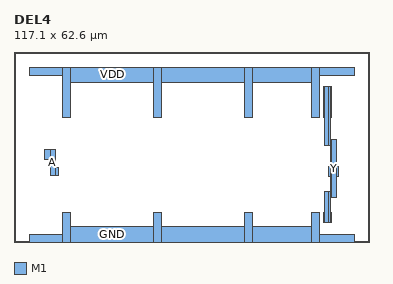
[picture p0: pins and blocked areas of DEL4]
MACRO DEL4
  CLASS CORE ;
  ORIGIN 0 0 ;
  SIZE 117.100 BY 62.600 ;
  SYMMETRY X Y ;
  SITE TR1um_site ;
  PIN VDD
    DIRECTION INOUT ;
    USE POWER ;
    PORT
      LAYER M1 ;
        RECT 5.000 55.000 16.100 57.600 ;
      LAYER M1 ;
        RECT 16.100 41.000 18.700 57.600 ;
      LAYER M1 ;
        RECT 18.700 52.600 46.100 57.600 ;
      LAYER M1 ;
        RECT 46.100 41.000 48.700 57.600 ;
      LAYER M1 ;
        RECT 48.700 52.600 76.100 57.600 ;
      LAYER M1 ;
        RECT 76.100 41.000 78.700 57.600 ;
      LAYER M1 ;
        RECT 78.700 52.600 98.100 57.600 ;
      LAYER M1 ;
        RECT 98.100 41.000 100.700 57.600 ;
      LAYER M1 ;
        RECT 100.700 55.000 112.100 57.600 ;
    END
  END VDD
  PIN Y
    DIRECTION OUTPUT ;
    USE SIGNAL ;
    PORT
      LAYER M1 ;
        RECT 102.100 6.400 102.400 9.800 ;
      LAYER M1 ;
        RECT 102.100 41.000 102.400 51.200 ;
      LAYER M1 ;
        RECT 102.400 6.400 103.600 16.600 ;
      LAYER M1 ;
        RECT 102.400 31.800 103.600 51.200 ;
      LAYER M1 ;
        RECT 103.600 6.400 104.300 16.600 ;
      LAYER M1 ;
        RECT 103.600 21.600 104.300 25.000 ;
      LAYER M1 ;
        RECT 103.600 31.800 104.300 51.200 ;
      LAYER M1 ;
        RECT 104.300 6.400 104.400 51.200 ;
      LAYER M1 ;
        RECT 104.400 6.400 104.700 9.800 ;
      LAYER M1 ;
        RECT 104.400 14.600 104.700 33.800 ;
      LAYER M1 ;
        RECT 104.400 41.000 104.700 51.200 ;
      LAYER M1 ;
        RECT 104.700 14.600 106.300 33.800 ;
      LAYER M1 ;
        RECT 106.300 21.600 107.000 25.000 ;
    END
  END Y
  PIN A
    DIRECTION INPUT ;
    USE SIGNAL ;
    PORT
      LAYER M1 ;
        RECT 10.100 27.100 11.900 30.500 ;
      LAYER M1 ;
        RECT 11.900 22.000 13.700 30.500 ;
      LAYER M1 ;
        RECT 13.700 22.000 14.500 24.600 ;
    END
  END A
  PIN GND
    DIRECTION INOUT ;
    USE GROUND ;
    PORT
      LAYER M1 ;
        RECT 5.000 0.000 16.100 2.600 ;
      LAYER M1 ;
        RECT 16.100 0.000 18.700 9.800 ;
      LAYER M1 ;
        RECT 18.700 0.000 46.100 5.000 ;
      LAYER M1 ;
        RECT 46.100 0.000 48.700 9.800 ;
      LAYER M1 ;
        RECT 48.700 0.000 76.100 5.000 ;
      LAYER M1 ;
        RECT 76.100 0.000 78.700 9.800 ;
      LAYER M1 ;
        RECT 78.700 0.000 98.100 5.000 ;
      LAYER M1 ;
        RECT 98.100 0.000 100.700 9.800 ;
      LAYER M1 ;
        RECT 100.700 0.000 112.100 2.600 ;
    END
  END GND
END DEL4
